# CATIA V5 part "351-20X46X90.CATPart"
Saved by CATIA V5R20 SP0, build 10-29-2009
Part number: 351-20X46X90
Definition: NONE
Nomenclature: 351-20X46X90
Source: Unknown
Description: 351-20X46X90
Bounding box of the stored display mesh (mm): x -6 to 84, y -16 to 16, z -16 to 16
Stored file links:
  C:\Users\Utente\Desktop\IO LAVORO\3D X SITO CF\X SITO\PLASTICA\351\351-20X46X90.CATPart

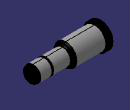
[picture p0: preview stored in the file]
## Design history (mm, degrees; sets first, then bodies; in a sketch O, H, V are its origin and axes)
Body1 "351-20X46X90" (main body)
  Solid1: solid without history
